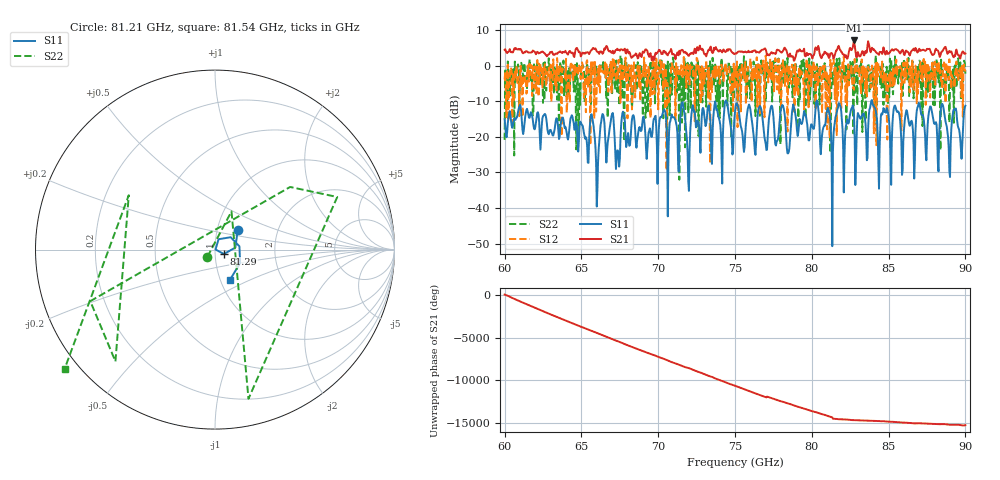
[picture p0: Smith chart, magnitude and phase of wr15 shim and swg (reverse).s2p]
!Created with skrf (http://scikit-rf.org).
# GHz S RI R 50.0
!freq ReS11 ImS11 ReS21 ImS21 ReS12 ImS12 ReS22 ImS22
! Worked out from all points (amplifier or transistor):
!   721 points, 60 GHz to 90 GHz, reference 50 ohm
!   highest |S21| = 7.1 dB at 82.75 GHz (marker M1)
!   |S21| within 3 dB of that: 86.93 GHz to 87.73 GHz (797.1 MHz wide, 0.913 % of centre) (the widest 1 of 52)
!   unconditionally stable (mu >= 1): 60.0732 GHz to 60.10893 GHz; 68.26541 GHz to 68.34492 GHz; 70.51677 GHz to 70.58821 GHz (the widest 3 of 33)
!   at 65 GHz: K = 0.82, MSG = 1.9 dB, |S12| = -0.8 dB
!   at 75 GHz: K = 0.84, MSG = 4.9 dB, |S12| = -6.4 dB
!   at 90 GHz: K = 0.94, MSG = 2.5 dB, |S12| = -1.7 dB
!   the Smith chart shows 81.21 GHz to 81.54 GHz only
!   S11 on the Smith chart (normalised r, x): 81.21 GHz: 1.25, +0.29; 81.29 GHz: 1.10, -0.05; 81.54 GHz: 1.11, -0.39
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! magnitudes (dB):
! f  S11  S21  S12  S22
! 60 GHz  -15.1  4.4  -3.9  -20.8
! 60.79 GHz  -14.6  4.6  -0.8  -1.7
! 65 GHz  -16.4  2.9  -0.8  -1.4
! 65.71 GHz  -14.7  4.5  -2.5  -0.2
! 66.04 GHz  -34.9  3.9  -2.6  -2.2
! 66.38 GHz  -13.6  3.3  -1.8  -1.1
! 67.38 GHz  -23.9  4.4  -3.6  -1.5
! 67.71 GHz  -12.9  4.3  0.0  -0.9
! 70 GHz  -23.5  3.9  -12.3  -1.8
! 70.67 GHz  -24.8  3.5  -10.4  -4.7
! 70.96 GHz  -14.5  3.3  -0.7  2.3
! 75 GHz  -13.1  3.4  -6.4  -3.6
! 80 GHz  -16.5  2.6  -0.1  1.0
! 81.21 GHz  -15.4  3.4  1.6  -24.5
! 81.29 GHz  -25.1  3.5  -0.2  -1.4
! 81.54 GHz  -14.5  3.6  -0.5  0.6
! 82.75 GHz  -14.1  7.1  -6.8  -1.2
! 85 GHz  -14.3  3.4  -2.9  -1.6
! 88.21 GHz  -27.4  4.2  -2.3  -0.4
! 88.5 GHz  -10.8  4.0  -6.6  -1.3
! 88.96 GHz  -29.7  4.1  1.8  -16.0
! 90 GHz  -11.3  3.4  -1.7  -2.3
